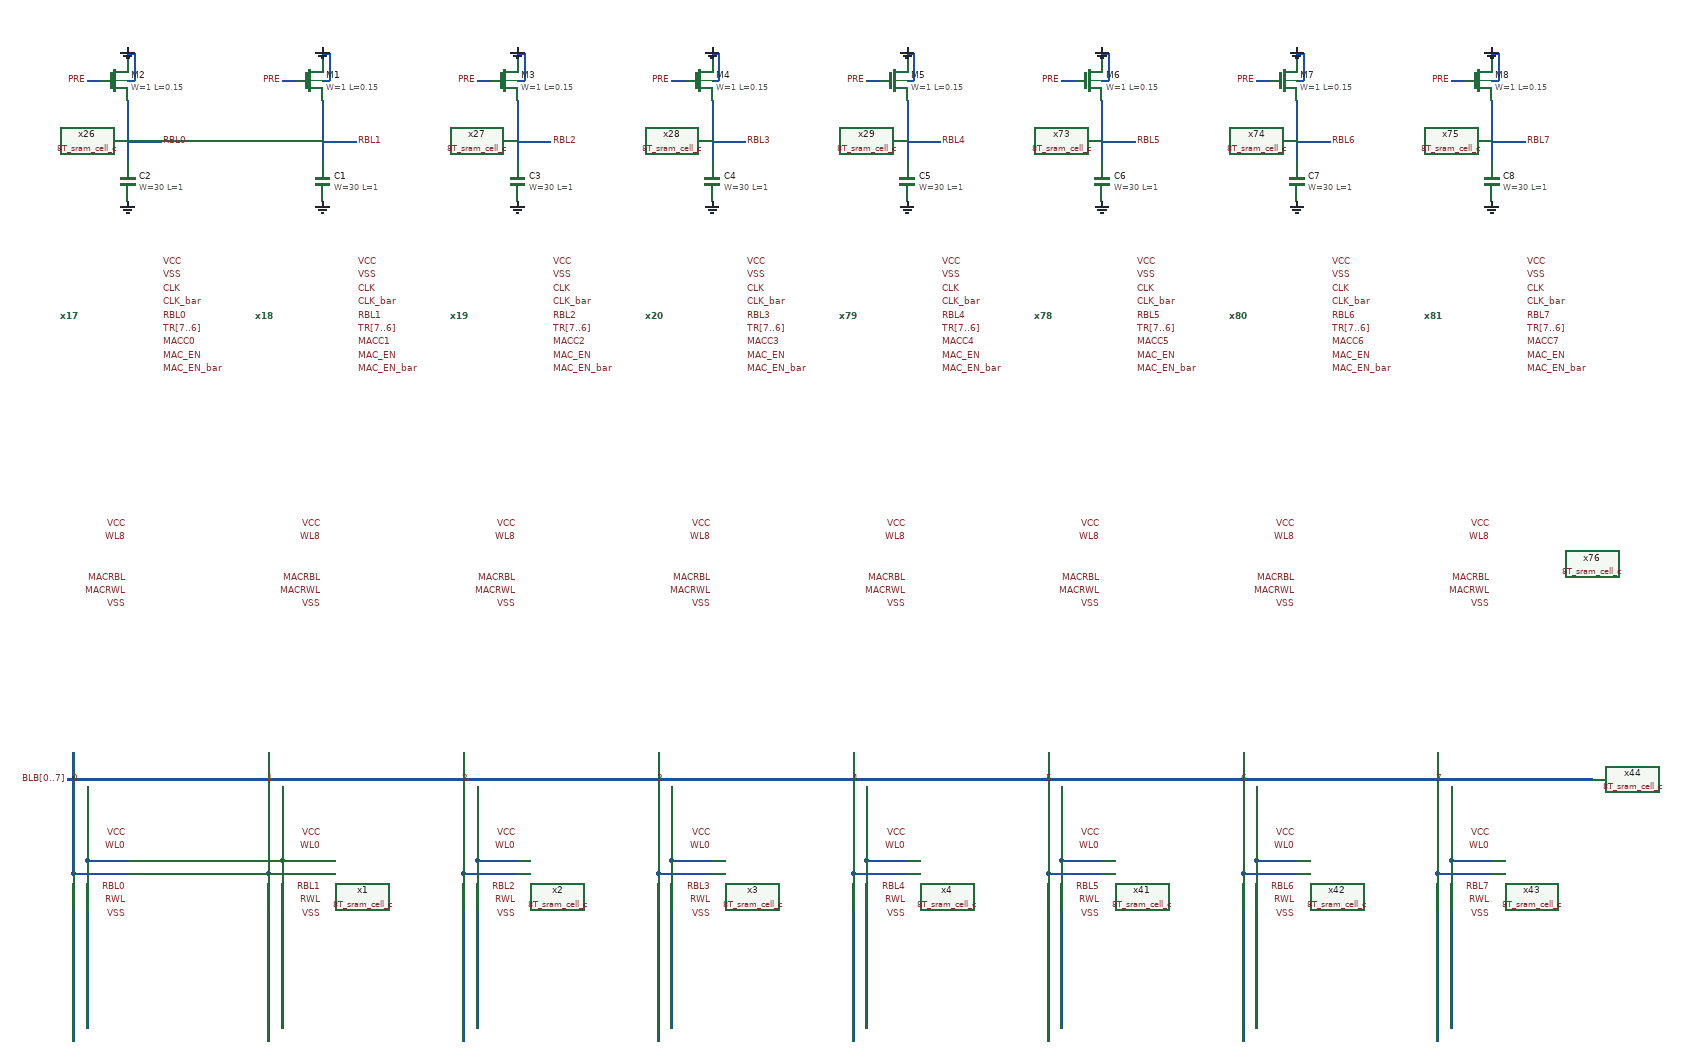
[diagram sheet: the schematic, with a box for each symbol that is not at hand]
v {xschem version=3.4.8RC file_version=1.3}
G {}
K {}
V {}
S {}
F {}
E {}
N 940 -3210 940 -3120 {lab=RBL0}
N 940 -3150 990 -3150 {lab=RBL0}
N 940 -3290 940 -3270 {lab=GND}
N 940 -3240 950 -3240 {lab=GND}
N 950 -3280 950 -3240 {lab=GND}
N 940 -3280 950 -3280 {lab=GND}
N 880 -3240 900 -3240 {lab=PRE}
N 1230 -3210 1230 -3120 {lab=RBL1}
N 1230 -3150 1280 -3150 {lab=RBL1}
N 1230 -3290 1230 -3270 {lab=GND}
N 1230 -3240 1240 -3240 {lab=GND}
N 1240 -3280 1240 -3240 {lab=GND}
N 1230 -3280 1240 -3280 {lab=GND}
N 1170 -3240 1190 -3240 {lab=PRE}
N 1520 -3210 1520 -3120 {lab=RBL2}
N 1520 -3150 1570 -3150 {lab=RBL2}
N 1520 -3290 1520 -3270 {lab=GND}
N 1520 -3240 1530 -3240 {lab=GND}
N 1530 -3280 1530 -3240 {lab=GND}
N 1520 -3280 1530 -3280 {lab=GND}
N 1460 -3240 1480 -3240 {lab=PRE}
N 1810 -3210 1810 -3120 {lab=RBL3}
N 1810 -3290 1810 -3270 {lab=GND}
N 1810 -3240 1820 -3240 {lab=GND}
N 1820 -3280 1820 -3240 {lab=GND}
N 1810 -3280 1820 -3280 {lab=GND}
N 1750 -3240 1770 -3240 {lab=PRE}
N 1810 -3150 1860 -3150 {lab=RBL3}
N 2100 -3210 2100 -3120 {lab=RBL4}
N 2100 -3150 2150 -3150 {lab=RBL4}
N 2100 -3290 2100 -3270 {lab=GND}
N 2100 -3240 2110 -3240 {lab=GND}
N 2110 -3280 2110 -3240 {lab=GND}
N 2100 -3280 2110 -3280 {lab=GND}
N 2040 -3240 2060 -3240 {lab=PRE}
N 2390 -3210 2390 -3120 {lab=RBL5}
N 2390 -3150 2440 -3150 {lab=RBL5}
N 2390 -3290 2390 -3270 {lab=GND}
N 2390 -3240 2400 -3240 {lab=GND}
N 2400 -3280 2400 -3240 {lab=GND}
N 2390 -3280 2400 -3280 {lab=GND}
N 2330 -3240 2350 -3240 {lab=PRE}
N 2680 -3210 2680 -3120 {lab=RBL6}
N 2680 -3150 2730 -3150 {lab=RBL6}
N 2680 -3290 2680 -3270 {lab=GND}
N 2680 -3240 2690 -3240 {lab=GND}
N 2690 -3280 2690 -3240 {lab=GND}
N 2680 -3280 2690 -3280 {lab=GND}
N 2620 -3240 2640 -3240 {lab=PRE}
N 2970 -3210 2970 -3120 {lab=RBL7}
N 2970 -3290 2970 -3270 {lab=GND}
N 2970 -3240 2980 -3240 {lab=GND}
N 2980 -3280 2980 -3240 {lab=GND}
N 2970 -3280 2980 -3280 {lab=GND}
N 2910 -3240 2930 -3240 {lab=PRE}
N 2970 -3150 3020 -3150 {lab=RBL7}
N 850 -2200 3120 -2200 {lab=BLB[0..7]
bus=true}
N 880 -2190 880 -2080 {lab=BLB0}
N 880 -2080 940 -2080 {lab=BLB0}
N 860 -2240 860 -2060 {lab=BL0
bus}
N 860 -2060 940 -2060 {lab=BL0}
N 1170 -2190 1170 -2080 {lab=BLB1}
N 1170 -2080 1230 -2080 {lab=BLB1}
N 1150 -2240 1150 -2060 {lab=BL1}
N 1150 -2060 1230 -2060 {lab=BL1}
N 1460 -2190 1460 -2080 {lab=BLB2}
N 1460 -2080 1520 -2080 {lab=BLB2}
N 1440 -2240 1440 -2060 {lab=BL2}
N 1440 -2060 1520 -2060 {lab=BL2}
N 1750 -2190 1750 -2080 {lab=BLB3}
N 1750 -2080 1810 -2080 {lab=BLB3}
N 1730 -2240 1730 -2060 {lab=BL3}
N 1730 -2060 1810 -2060 {lab=BL3}
N 860 -2060 860 -1810 {lab=BL0}
N 880 -2080 880 -1830 {lab=BLB0}
N 1150 -2060 1150 -1810 {lab=BL1}
N 1170 -2080 1170 -1830 {lab=BLB1}
N 1440 -2060 1440 -1810 {lab=BL2}
N 1460 -2080 1460 -1830 {lab=BLB2}
N 1730 -2060 1730 -1810 {lab=BL3}
N 1750 -2080 1750 -1830 {lab=BLB3}
N 2040 -2190 2040 -2080 {lab=BLB4}
N 2040 -2080 2100 -2080 {lab=BLB4}
N 2020 -2240 2020 -2060 {lab=BL4}
N 2020 -2060 2100 -2060 {lab=BL4}
N 2330 -2190 2330 -2080 {lab=BLB5}
N 2330 -2080 2390 -2080 {lab=BLB5}
N 2310 -2240 2310 -2060 {lab=BL5}
N 2310 -2060 2390 -2060 {lab=BL5}
N 2620 -2190 2620 -2080 {lab=BLB6}
N 2620 -2080 2680 -2080 {lab=BLB6}
N 2600 -2240 2600 -2060 {lab=BL6}
N 2600 -2060 2680 -2060 {lab=BL6}
N 2910 -2190 2910 -2080 {lab=BLB7}
N 2910 -2080 2970 -2080 {lab=BLB7}
N 2890 -2240 2890 -2060 {lab=BL7}
N 2890 -2060 2970 -2060 {lab=BL7}
N 2020 -2060 2020 -1810 {lab=BL4}
N 2040 -2080 2040 -1830 {lab=BLB4}
N 2310 -2060 2310 -1810 {lab=BL5}
N 2330 -2080 2330 -1830 {lab=BLB5}
N 2600 -2060 2600 -1810 {lab=BL6}
N 2620 -2080 2620 -1830 {lab=BLB6}
N 2890 -2060 2890 -1810 {lab=BL7}
N 2910 -2080 2910 -1830 {lab=BLB7}
C {lab_pin.sym} 940 -2460 0 0 {name=p214 sig_type=std_logic lab=VSS}
C {lab_pin.sym} 940 -2480 0 0 {name=p215 sig_type=std_logic lab=MACRWL}
C {lab_pin.sym} 1230 -2460 0 0 {name=p216 sig_type=std_logic lab=VSS}
C {8T_sram_cell_c.sym} 1090 -2520 0 1 {name=x26}
C {lab_pin.sym} 1230 -2480 0 0 {name=p217 sig_type=std_logic lab=MACRWL}
C {lab_pin.sym} 1520 -2460 0 0 {name=p218 sig_type=std_logic lab=VSS}
C {8T_sram_cell_c.sym} 1380 -2520 0 1 {name=x27}
C {lab_pin.sym} 1520 -2480 0 0 {name=p219 sig_type=std_logic lab=MACRWL}
C {lab_pin.sym} 1810 -2460 0 0 {name=p220 sig_type=std_logic lab=VSS}
C {8T_sram_cell_c.sym} 1670 -2520 0 1 {name=x28}
C {lab_pin.sym} 1810 -2480 0 0 {name=p221 sig_type=std_logic lab=MACRWL}
C {8T_sram_cell_c.sym} 1960 -2520 0 1 {name=x29}
C {lab_pin.sym} 940 -2580 0 0 {name=p230 sig_type=std_logic lab=VCC}
C {lab_pin.sym} 1230 -2580 0 0 {name=p231 sig_type=std_logic lab=VCC}
C {lab_pin.sym} 1520 -2580 0 0 {name=p232 sig_type=std_logic lab=VCC}
C {lab_pin.sym} 1810 -2580 0 0 {name=p233 sig_type=std_logic lab=VCC}
C {lab_pin.sym} 940 -2560 0 0 {name=p238 sig_type=std_logic lab=WL8}
C {lab_pin.sym} 1230 -2560 0 0 {name=p239 sig_type=std_logic lab=WL8}
C {lab_pin.sym} 1520 -2560 0 0 {name=p240 sig_type=std_logic lab=WL8}
C {lab_pin.sym} 1810 -2560 0 0 {name=p241 sig_type=std_logic lab=WL8}
C {lab_pin.sym} 1810 -2500 0 0 {name=p250 sig_type=std_logic lab=MACRBL}
C {lab_pin.sym} 1520 -2500 0 0 {name=p251 sig_type=std_logic lab=MACRBL}
C {lab_pin.sym} 1230 -2500 0 0 {name=p252 sig_type=std_logic lab=MACRBL}
C {lab_pin.sym} 940 -2500 0 0 {name=p253 sig_type=std_logic lab=MACRBL}
C {lab_pin.sym} 2100 -2460 0 0 {name=p444 sig_type=std_logic lab=VSS}
C {lab_pin.sym} 2100 -2480 0 0 {name=p445 sig_type=std_logic lab=MACRWL}
C {lab_pin.sym} 2390 -2460 0 0 {name=p446 sig_type=std_logic lab=VSS}
C {8T_sram_cell_c.sym} 2250 -2520 0 1 {name=x73}
C {lab_pin.sym} 2390 -2480 0 0 {name=p447 sig_type=std_logic lab=MACRWL}
C {lab_pin.sym} 2680 -2460 0 0 {name=p448 sig_type=std_logic lab=VSS}
C {8T_sram_cell_c.sym} 2540 -2520 0 1 {name=x74}
C {lab_pin.sym} 2680 -2480 0 0 {name=p449 sig_type=std_logic lab=MACRWL}
C {lab_pin.sym} 2970 -2460 0 0 {name=p450 sig_type=std_logic lab=VSS}
C {8T_sram_cell_c.sym} 2830 -2520 0 1 {name=x75}
C {lab_pin.sym} 2970 -2480 0 0 {name=p451 sig_type=std_logic lab=MACRWL}
C {8T_sram_cell_c.sym} 3120 -2520 0 1 {name=x76}
C {lab_pin.sym} 2100 -2580 0 0 {name=p452 sig_type=std_logic lab=VCC}
C {lab_pin.sym} 2390 -2580 0 0 {name=p453 sig_type=std_logic lab=VCC}
C {lab_pin.sym} 2680 -2580 0 0 {name=p454 sig_type=std_logic lab=VCC}
C {lab_pin.sym} 2970 -2580 0 0 {name=p455 sig_type=std_logic lab=VCC}
C {lab_pin.sym} 2100 -2560 0 0 {name=p456 sig_type=std_logic lab=WL8}
C {lab_pin.sym} 2390 -2560 0 0 {name=p457 sig_type=std_logic lab=WL8}
C {lab_pin.sym} 2680 -2560 0 0 {name=p458 sig_type=std_logic lab=WL8}
C {lab_pin.sym} 2970 -2560 0 0 {name=p459 sig_type=std_logic lab=WL8}
C {lab_pin.sym} 2970 -2500 0 0 {name=p460 sig_type=std_logic lab=MACRBL}
C {lab_pin.sym} 2680 -2500 0 0 {name=p461 sig_type=std_logic lab=MACRBL}
C {lab_pin.sym} 2390 -2500 0 0 {name=p462 sig_type=std_logic lab=MACRBL}
C {lab_pin.sym} 2100 -2500 0 0 {name=p463 sig_type=std_logic lab=MACRBL}
C {sky130_fd_pr/cap_mim_m3_1.sym} 940 -3090 0 0 {name=C2 model=cap_mim_m3_1 W=30 L=1 MF=1 spiceprefix=X}
C {gnd.sym} 940 -3290 2 0 {name=l1 lab=GND}
C {sky130_fd_pr/nfet_01v8.sym} 920 -3240 2 1 {name=M2
W=1
L=0.15
nf=1 
mult=1
ad="expr('int((@nf + 1)/2) * @W / @nf * 0.29')"
pd="expr('2*int((@nf + 1)/2) * (@W / @nf + 0.29)')"
as="expr('int((@nf + 2)/2) * @W / @nf * 0.29')"
ps="expr('2*int((@nf + 2)/2) * (@W / @nf + 0.29)')"
nrd="expr('0.29 / @W ')" nrs="expr('0.29 / @W ')"
sa=0 sb=0 sd=0
model=nfet_01v8
spiceprefix=X
}
C {gnd.sym} 940 -3060 0 1 {name=l10 lab=GND}
C {lab_pin.sym} 880 -3240 0 0 {name=p96 sig_type=std_logic lab=PRE}
C {sky130_fd_pr/cap_mim_m3_1.sym} 1230 -3090 0 0 {name=C1 model=cap_mim_m3_1 W=30 L=1 MF=1 spiceprefix=X}
C {gnd.sym} 1230 -3290 2 0 {name=l27 lab=GND}
C {sky130_fd_pr/nfet_01v8.sym} 1210 -3240 2 1 {name=M1
W=1
L=0.15
nf=1 
mult=1
ad="expr('int((@nf + 1)/2) * @W / @nf * 0.29')"
pd="expr('2*int((@nf + 1)/2) * (@W / @nf + 0.29)')"
as="expr('int((@nf + 2)/2) * @W / @nf * 0.29')"
ps="expr('2*int((@nf + 2)/2) * (@W / @nf + 0.29)')"
nrd="expr('0.29 / @W ')" nrs="expr('0.29 / @W ')"
sa=0 sb=0 sd=0
model=nfet_01v8
spiceprefix=X
}
C {gnd.sym} 1230 -3060 0 1 {name=l28 lab=GND}
C {lab_pin.sym} 1170 -3240 0 0 {name=p99 sig_type=std_logic lab=PRE}
C {sky130_fd_pr/cap_mim_m3_1.sym} 1520 -3090 0 0 {name=C3 model=cap_mim_m3_1 W=30 L=1 MF=1 spiceprefix=X}
C {gnd.sym} 1520 -3290 2 0 {name=l29 lab=GND}
C {sky130_fd_pr/nfet_01v8.sym} 1500 -3240 2 1 {name=M3
W=1
L=0.15
nf=1 
mult=1
ad="expr('int((@nf + 1)/2) * @W / @nf * 0.29')"
pd="expr('2*int((@nf + 1)/2) * (@W / @nf + 0.29)')"
as="expr('int((@nf + 2)/2) * @W / @nf * 0.29')"
ps="expr('2*int((@nf + 2)/2) * (@W / @nf + 0.29)')"
nrd="expr('0.29 / @W ')" nrs="expr('0.29 / @W ')"
sa=0 sb=0 sd=0
model=nfet_01v8
spiceprefix=X
}
C {gnd.sym} 1520 -3060 0 1 {name=l30 lab=GND}
C {lab_pin.sym} 1460 -3240 0 0 {name=p119 sig_type=std_logic lab=PRE}
C {sky130_fd_pr/cap_mim_m3_1.sym} 1810 -3090 0 0 {name=C4 model=cap_mim_m3_1 W=30 L=1 MF=1 spiceprefix=X}
C {gnd.sym} 1810 -3290 2 0 {name=l31 lab=GND}
C {sky130_fd_pr/nfet_01v8.sym} 1790 -3240 2 1 {name=M4
W=1
L=0.15
nf=1 
mult=1
ad="expr('int((@nf + 1)/2) * @W / @nf * 0.29')"
pd="expr('2*int((@nf + 1)/2) * (@W / @nf + 0.29)')"
as="expr('int((@nf + 2)/2) * @W / @nf * 0.29')"
ps="expr('2*int((@nf + 2)/2) * (@W / @nf + 0.29)')"
nrd="expr('0.29 / @W ')" nrs="expr('0.29 / @W ')"
sa=0 sb=0 sd=0
model=nfet_01v8
spiceprefix=X
}
C {gnd.sym} 1810 -3060 0 1 {name=l32 lab=GND}
C {lab_pin.sym} 1750 -3240 0 0 {name=p121 sig_type=std_logic lab=PRE}
C {lab_pin.sym} 1860 -3150 0 1 {name=p122 sig_type=std_logic lab=RBL3}
C {lab_pin.sym} 1570 -3150 0 1 {name=p124 sig_type=std_logic lab=RBL2}
C {lab_pin.sym} 1280 -3150 0 1 {name=p126 sig_type=std_logic lab=RBL1}
C {lab_pin.sym} 990 -3150 0 1 {name=p128 sig_type=std_logic lab=RBL0}
C {voltage_comp/MAC_decoder_7.sym} 1130 -2890 0 0 {name=x18}
C {lab_pin.sym} 990 -2950 0 1 {name=p139 sig_type=std_logic lab=VSS}
C {lab_pin.sym} 990 -2970 0 1 {name=p140 sig_type=std_logic lab=VCC}
C {lab_pin.sym} 990 -2930 0 1 {name=p141 sig_type=std_logic lab=CLK}
C {lab_pin.sym} 990 -2910 0 1 {name=p142 sig_type=std_logic lab=CLK_bar}
C {lab_pin.sym} 990 -2850 0 1 {name=p143 sig_type=std_logic lab=MACC0}
C {lab_pin.sym} 990 -2870 0 1 {name=p144 sig_type=std_logic lab=TR[7..6]}
C {voltage_comp/MAC_decoder_7.sym} 840 -2890 0 0 {name=x17}
C {lab_pin.sym} 1280 -2950 0 1 {name=p150 sig_type=std_logic lab=VSS}
C {lab_pin.sym} 1280 -2970 0 1 {name=p151 sig_type=std_logic lab=VCC}
C {lab_pin.sym} 1280 -2930 0 1 {name=p152 sig_type=std_logic lab=CLK}
C {lab_pin.sym} 1280 -2910 0 1 {name=p153 sig_type=std_logic lab=CLK_bar}
C {lab_pin.sym} 1280 -2850 0 1 {name=p154 sig_type=std_logic lab=MACC1}
C {lab_pin.sym} 1280 -2870 0 1 {name=p155 sig_type=std_logic lab=TR[7..6]}
C {voltage_comp/MAC_decoder_7.sym} 1420 -2890 0 0 {name=x19}
C {lab_pin.sym} 1570 -2950 0 1 {name=p159 sig_type=std_logic lab=VSS}
C {lab_pin.sym} 1570 -2970 0 1 {name=p160 sig_type=std_logic lab=VCC}
C {lab_pin.sym} 1570 -2930 0 1 {name=p161 sig_type=std_logic lab=CLK}
C {lab_pin.sym} 1570 -2910 0 1 {name=p162 sig_type=std_logic lab=CLK_bar}
C {lab_pin.sym} 1570 -2850 0 1 {name=p163 sig_type=std_logic lab=MACC2}
C {lab_pin.sym} 1570 -2870 0 1 {name=p164 sig_type=std_logic lab=TR[7..6]}
C {voltage_comp/MAC_decoder_7.sym} 1710 -2890 0 0 {name=x20}
C {lab_pin.sym} 1860 -2950 0 1 {name=p168 sig_type=std_logic lab=VSS}
C {lab_pin.sym} 1860 -2970 0 1 {name=p169 sig_type=std_logic lab=VCC}
C {lab_pin.sym} 1860 -2930 0 1 {name=p170 sig_type=std_logic lab=CLK}
C {lab_pin.sym} 1860 -2910 0 1 {name=p171 sig_type=std_logic lab=CLK_bar}
C {lab_pin.sym} 1860 -2850 0 1 {name=p172 sig_type=std_logic lab=MACC3}
C {lab_pin.sym} 1860 -2870 0 1 {name=p173 sig_type=std_logic lab=TR[7..6]}
C {lab_pin.sym} 1860 -2890 0 1 {name=p174 sig_type=std_logic lab=RBL3}
C {lab_pin.sym} 1570 -2890 0 1 {name=p183 sig_type=std_logic lab=RBL2}
C {lab_pin.sym} 1280 -2890 0 1 {name=p192 sig_type=std_logic lab=RBL1}
C {lab_pin.sym} 990 -2890 0 1 {name=p201 sig_type=std_logic lab=RBL0}
C {lab_pin.sym} 990 -2810 0 1 {name=p285 sig_type=std_logic lab=MAC_EN_bar}
C {lab_pin.sym} 990 -2830 0 1 {name=p286 lab=MAC_EN}
C {lab_pin.sym} 1280 -2810 0 1 {name=p287 sig_type=std_logic lab=MAC_EN_bar}
C {lab_pin.sym} 1280 -2830 0 1 {name=p288 lab=MAC_EN}
C {lab_pin.sym} 1570 -2810 0 1 {name=p289 sig_type=std_logic lab=MAC_EN_bar}
C {lab_pin.sym} 1570 -2830 0 1 {name=p290 lab=MAC_EN}
C {lab_pin.sym} 1860 -2810 0 1 {name=p291 sig_type=std_logic lab=MAC_EN_bar}
C {lab_pin.sym} 1860 -2830 0 1 {name=p292 lab=MAC_EN}
C {sky130_fd_pr/cap_mim_m3_1.sym} 2100 -3090 0 0 {name=C5 model=cap_mim_m3_1 W=30 L=1 MF=1 spiceprefix=X}
C {gnd.sym} 2100 -3290 2 0 {name=l44 lab=GND}
C {sky130_fd_pr/nfet_01v8.sym} 2080 -3240 2 1 {name=M5
W=1
L=0.15
nf=1 
mult=1
ad="expr('int((@nf + 1)/2) * @W / @nf * 0.29')"
pd="expr('2*int((@nf + 1)/2) * (@W / @nf + 0.29)')"
as="expr('int((@nf + 2)/2) * @W / @nf * 0.29')"
ps="expr('2*int((@nf + 2)/2) * (@W / @nf + 0.29)')"
nrd="expr('0.29 / @W ')" nrs="expr('0.29 / @W ')"
sa=0 sb=0 sd=0
model=nfet_01v8
spiceprefix=X
}
C {gnd.sym} 2100 -3060 0 1 {name=l45 lab=GND}
C {lab_pin.sym} 2040 -3240 0 0 {name=p464 sig_type=std_logic lab=PRE}
C {sky130_fd_pr/cap_mim_m3_1.sym} 2390 -3090 0 0 {name=C6 model=cap_mim_m3_1 W=30 L=1 MF=1 spiceprefix=X}
C {gnd.sym} 2390 -3290 2 0 {name=l46 lab=GND}
C {sky130_fd_pr/nfet_01v8.sym} 2370 -3240 2 1 {name=M6
W=1
L=0.15
nf=1 
mult=1
ad="expr('int((@nf + 1)/2) * @W / @nf * 0.29')"
pd="expr('2*int((@nf + 1)/2) * (@W / @nf + 0.29)')"
as="expr('int((@nf + 2)/2) * @W / @nf * 0.29')"
ps="expr('2*int((@nf + 2)/2) * (@W / @nf + 0.29)')"
nrd="expr('0.29 / @W ')" nrs="expr('0.29 / @W ')"
sa=0 sb=0 sd=0
model=nfet_01v8
spiceprefix=X
}
C {gnd.sym} 2390 -3060 0 1 {name=l47 lab=GND}
C {lab_pin.sym} 2330 -3240 0 0 {name=p465 sig_type=std_logic lab=PRE}
C {sky130_fd_pr/cap_mim_m3_1.sym} 2680 -3090 0 0 {name=C7 model=cap_mim_m3_1 W=30 L=1 MF=1 spiceprefix=X}
C {gnd.sym} 2680 -3290 2 0 {name=l48 lab=GND}
C {sky130_fd_pr/nfet_01v8.sym} 2660 -3240 2 1 {name=M7
W=1
L=0.15
nf=1 
mult=1
ad="expr('int((@nf + 1)/2) * @W / @nf * 0.29')"
pd="expr('2*int((@nf + 1)/2) * (@W / @nf + 0.29)')"
as="expr('int((@nf + 2)/2) * @W / @nf * 0.29')"
ps="expr('2*int((@nf + 2)/2) * (@W / @nf + 0.29)')"
nrd="expr('0.29 / @W ')" nrs="expr('0.29 / @W ')"
sa=0 sb=0 sd=0
model=nfet_01v8
spiceprefix=X
}
C {gnd.sym} 2680 -3060 0 1 {name=l49 lab=GND}
C {lab_pin.sym} 2620 -3240 0 0 {name=p466 sig_type=std_logic lab=PRE}
C {sky130_fd_pr/cap_mim_m3_1.sym} 2970 -3090 0 0 {name=C8 model=cap_mim_m3_1 W=30 L=1 MF=1 spiceprefix=X}
C {gnd.sym} 2970 -3290 2 0 {name=l50 lab=GND}
C {sky130_fd_pr/nfet_01v8.sym} 2950 -3240 2 1 {name=M8
W=1
L=0.15
nf=1 
mult=1
ad="expr('int((@nf + 1)/2) * @W / @nf * 0.29')"
pd="expr('2*int((@nf + 1)/2) * (@W / @nf + 0.29)')"
as="expr('int((@nf + 2)/2) * @W / @nf * 0.29')"
ps="expr('2*int((@nf + 2)/2) * (@W / @nf + 0.29)')"
nrd="expr('0.29 / @W ')" nrs="expr('0.29 / @W ')"
sa=0 sb=0 sd=0
model=nfet_01v8
spiceprefix=X
}
C {gnd.sym} 2970 -3060 0 1 {name=l55 lab=GND}
C {lab_pin.sym} 2910 -3240 0 0 {name=p467 sig_type=std_logic lab=PRE}
C {lab_pin.sym} 3020 -3150 0 1 {name=p468 sig_type=std_logic lab=RBL7}
C {lab_pin.sym} 2730 -3150 0 1 {name=p469 sig_type=std_logic lab=RBL6}
C {lab_pin.sym} 2440 -3150 0 1 {name=p470 sig_type=std_logic lab=RBL5}
C {lab_pin.sym} 2150 -3150 0 1 {name=p471 sig_type=std_logic lab=RBL4}
C {voltage_comp/MAC_decoder_7.sym} 2290 -2890 0 0 {name=x78}
C {lab_pin.sym} 2150 -2950 0 1 {name=p472 sig_type=std_logic lab=VSS}
C {lab_pin.sym} 2150 -2970 0 1 {name=p473 sig_type=std_logic lab=VCC}
C {lab_pin.sym} 2150 -2930 0 1 {name=p474 sig_type=std_logic lab=CLK}
C {lab_pin.sym} 2150 -2910 0 1 {name=p475 sig_type=std_logic lab=CLK_bar}
C {lab_pin.sym} 2150 -2850 0 1 {name=p476 sig_type=std_logic lab=MACC4}
C {lab_pin.sym} 2150 -2870 0 1 {name=p477 sig_type=std_logic lab=TR[7..6]}
C {voltage_comp/MAC_decoder_7.sym} 2000 -2890 0 0 {name=x79}
C {lab_pin.sym} 2440 -2950 0 1 {name=p478 sig_type=std_logic lab=VSS}
C {lab_pin.sym} 2440 -2970 0 1 {name=p479 sig_type=std_logic lab=VCC}
C {lab_pin.sym} 2440 -2930 0 1 {name=p480 sig_type=std_logic lab=CLK}
C {lab_pin.sym} 2440 -2910 0 1 {name=p481 sig_type=std_logic lab=CLK_bar}
C {lab_pin.sym} 2440 -2850 0 1 {name=p482 sig_type=std_logic lab=MACC5}
C {lab_pin.sym} 2440 -2870 0 1 {name=p483 sig_type=std_logic lab=TR[7..6]}
C {voltage_comp/MAC_decoder_7.sym} 2580 -2890 0 0 {name=x80}
C {lab_pin.sym} 2730 -2950 0 1 {name=p484 sig_type=std_logic lab=VSS}
C {lab_pin.sym} 2730 -2970 0 1 {name=p485 sig_type=std_logic lab=VCC}
C {lab_pin.sym} 2730 -2930 0 1 {name=p486 sig_type=std_logic lab=CLK}
C {lab_pin.sym} 2730 -2910 0 1 {name=p487 sig_type=std_logic lab=CLK_bar}
C {lab_pin.sym} 2730 -2850 0 1 {name=p488 sig_type=std_logic lab=MACC6}
C {lab_pin.sym} 2730 -2870 0 1 {name=p489 sig_type=std_logic lab=TR[7..6]}
C {voltage_comp/MAC_decoder_7.sym} 2870 -2890 0 0 {name=x81}
C {lab_pin.sym} 3020 -2950 0 1 {name=p490 sig_type=std_logic lab=VSS}
C {lab_pin.sym} 3020 -2970 0 1 {name=p491 sig_type=std_logic lab=VCC}
C {lab_pin.sym} 3020 -2930 0 1 {name=p492 sig_type=std_logic lab=CLK}
C {lab_pin.sym} 3020 -2910 0 1 {name=p493 sig_type=std_logic lab=CLK_bar}
C {lab_pin.sym} 3020 -2850 0 1 {name=p494 sig_type=std_logic lab=MACC7}
C {lab_pin.sym} 3020 -2870 0 1 {name=p495 sig_type=std_logic lab=TR[7..6]}
C {lab_pin.sym} 2730 -2890 0 1 {name=p496 sig_type=std_logic lab=RBL6}
C {lab_pin.sym} 3020 -2890 0 1 {name=p497 sig_type=std_logic lab=RBL7}
C {lab_pin.sym} 2440 -2890 0 1 {name=p498 sig_type=std_logic lab=RBL5}
C {lab_pin.sym} 2150 -2890 0 1 {name=p499 sig_type=std_logic lab=RBL4}
C {lab_pin.sym} 2150 -2810 0 1 {name=p500 sig_type=std_logic lab=MAC_EN_bar}
C {lab_pin.sym} 2150 -2830 0 1 {name=p501 lab=MAC_EN}
C {lab_pin.sym} 2440 -2810 0 1 {name=p502 sig_type=std_logic lab=MAC_EN_bar}
C {lab_pin.sym} 2440 -2830 0 1 {name=p503 lab=MAC_EN}
C {lab_pin.sym} 2730 -2810 0 1 {name=p504 sig_type=std_logic lab=MAC_EN_bar}
C {lab_pin.sym} 2730 -2830 0 1 {name=p505 lab=MAC_EN}
C {lab_pin.sym} 3020 -2810 0 1 {name=p506 sig_type=std_logic lab=MAC_EN_bar}
C {lab_pin.sym} 3020 -2830 0 1 {name=p507 lab=MAC_EN}
C {lab_pin.sym} 940 -2100 0 0 {name=p1 sig_type=std_logic lab=WL0}
C {lab_pin.sym} 940 -2000 0 0 {name=p43 sig_type=std_logic lab=VSS}
C {lab_pin.sym} 940 -2120 0 0 {name=p51 sig_type=std_logic lab=VCC}
C {lab_pin.sym} 940 -2020 0 0 {name=p87 sig_type=std_logic lab=RWL}
C {lab_pin.sym} 1230 -2100 0 0 {name=p2 sig_type=std_logic lab=WL0}
C {lab_pin.sym} 1230 -2000 0 0 {name=p5 sig_type=std_logic lab=VSS}
C {lab_pin.sym} 1230 -2120 0 0 {name=p6 sig_type=std_logic lab=VCC}
C {8T_sram_cell_c.sym} 1090 -2060 0 1 {name=x1}
C {lab_pin.sym} 1230 -2020 0 0 {name=p15 sig_type=std_logic lab=RWL}
C {lab_pin.sym} 1520 -2100 0 0 {name=p28 sig_type=std_logic lab=WL0}
C {lab_pin.sym} 1520 -2000 0 0 {name=p31 sig_type=std_logic lab=VSS}
C {lab_pin.sym} 1520 -2120 0 0 {name=p32 sig_type=std_logic lab=VCC}
C {8T_sram_cell_c.sym} 1380 -2060 0 1 {name=x2}
C {lab_pin.sym} 1520 -2020 0 0 {name=p33 sig_type=std_logic lab=RWL}
C {lab_pin.sym} 1810 -2100 0 0 {name=p36 sig_type=std_logic lab=WL0}
C {lab_pin.sym} 1810 -2000 0 0 {name=p39 sig_type=std_logic lab=VSS}
C {lab_pin.sym} 1810 -2120 0 0 {name=p40 sig_type=std_logic lab=VCC}
C {8T_sram_cell_c.sym} 1670 -2060 0 1 {name=x3}
C {lab_pin.sym} 1810 -2020 0 0 {name=p41 sig_type=std_logic lab=RWL}
C {8T_sram_cell_c.sym} 1960 -2060 0 1 {name=x4}
C {lab_pin.sym} 1810 -2040 0 0 {name=p52 sig_type=std_logic lab=RBL3}
C {lab_pin.sym} 1520 -2040 0 0 {name=p88 sig_type=std_logic lab=RBL2}
C {lab_pin.sym} 1230 -2040 0 0 {name=p105 sig_type=std_logic lab=RBL1}
C {lab_pin.sym} 940 -2040 0 0 {name=p112 sig_type=std_logic lab=RBL0}
C {lab_pin.sym} 850 -2200 0 0 {name=p4 sig_type=std_logic lab=BLB[0..7]}
C {bus_tap.sym} 870 -2200 1 0 {name=l3 lab=0}
C {bus_tap.sym} 1160 -2200 1 0 {name=l5 lab=1}
C {bus_tap.sym} 1450 -2200 1 0 {name=l7 lab=2}
C {bus_tap.sym} 1740 -2200 1 0 {name=l9 lab=3}
C {8T_sram_cell_c.sym} 2250 -2060 0 1 {name=x41}
C {lab_pin.sym} 2970 -2040 0 0 {name=p267 sig_type=std_logic lab=RBL7}
C {lab_pin.sym} 2680 -2040 0 0 {name=p268 sig_type=std_logic lab=RBL6}
C {lab_pin.sym} 2390 -2040 0 0 {name=p269 sig_type=std_logic lab=RBL5}
C {lab_pin.sym} 2100 -2040 0 0 {name=p270 sig_type=std_logic lab=RBL4}
C {lab_pin.sym} 2100 -2100 0 0 {name=p271 sig_type=std_logic lab=WL0}
C {lab_pin.sym} 2100 -2000 0 0 {name=p272 sig_type=std_logic lab=VSS}
C {lab_pin.sym} 2100 -2120 0 0 {name=p273 sig_type=std_logic lab=VCC}
C {lab_pin.sym} 2100 -2020 0 0 {name=p274 sig_type=std_logic lab=RWL}
C {lab_pin.sym} 2390 -2100 0 0 {name=p275 sig_type=std_logic lab=WL0}
C {lab_pin.sym} 2390 -2000 0 0 {name=p276 sig_type=std_logic lab=VSS}
C {lab_pin.sym} 2390 -2120 0 0 {name=p293 sig_type=std_logic lab=VCC}
C {8T_sram_cell_c.sym} 2540 -2060 0 1 {name=x42}
C {lab_pin.sym} 2390 -2020 0 0 {name=p294 sig_type=std_logic lab=RWL}
C {lab_pin.sym} 2680 -2100 0 0 {name=p295 sig_type=std_logic lab=WL0}
C {lab_pin.sym} 2680 -2000 0 0 {name=p296 sig_type=std_logic lab=VSS}
C {lab_pin.sym} 2680 -2120 0 0 {name=p297 sig_type=std_logic lab=VCC}
C {8T_sram_cell_c.sym} 2830 -2060 0 1 {name=x43}
C {lab_pin.sym} 2680 -2020 0 0 {name=p298 sig_type=std_logic lab=RWL}
C {lab_pin.sym} 2970 -2100 0 0 {name=p299 sig_type=std_logic lab=WL0}
C {lab_pin.sym} 2970 -2000 0 0 {name=p300 sig_type=std_logic lab=VSS}
C {lab_pin.sym} 2970 -2120 0 0 {name=p301 sig_type=std_logic lab=VCC}
C {8T_sram_cell_c.sym} 3120 -2060 0 1 {name=x44}
C {lab_pin.sym} 2970 -2020 0 0 {name=p302 sig_type=std_logic lab=RWL}
C {bus_tap.sym} 2320 -2200 1 0 {name=l12 lab=5}
C {bus_tap.sym} 2610 -2200 1 0 {name=l14 lab=6}
C {bus_tap.sym} 2900 -2200 1 0 {name=l16 lab=7}
C {bus_tap.sym} 2030 -2200 1 0 {name=l18 lab=4}
